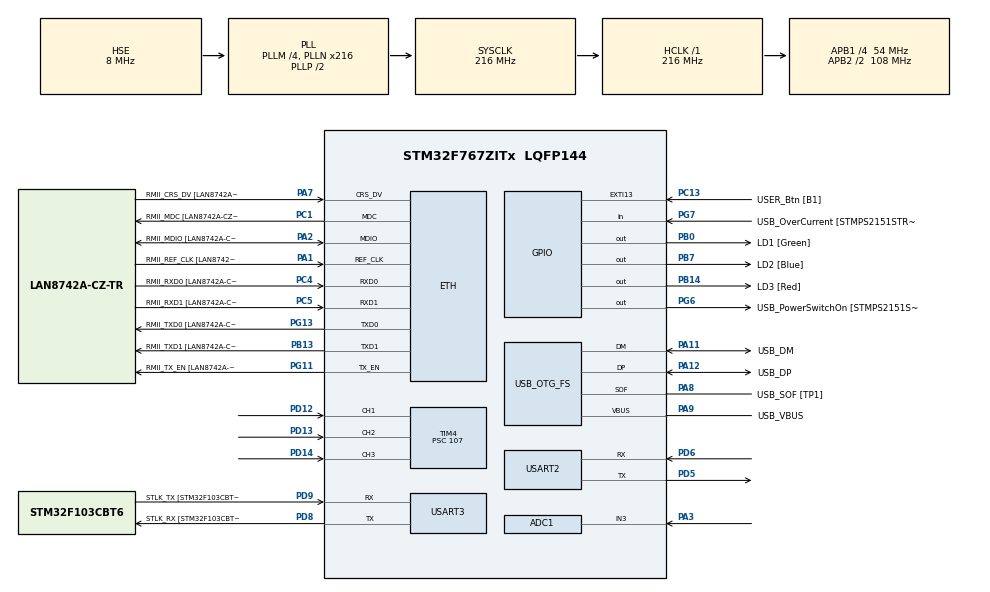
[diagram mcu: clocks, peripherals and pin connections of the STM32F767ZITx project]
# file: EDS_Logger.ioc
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ADC1.Channel-0\#ChannelRegularConversion=ADC_CHANNEL_3
ADC1.ClockPrescaler=ADC_CLOCK_SYNC_PCLK_DIV8
ADC1.ContinuousConvMode=ENABLE
ADC1.DMAContinuousRequests=ENABLE
ADC1.EOCSelection=ADC_EOC_SEQ_CONV
ADC1.ExternalTrigConv=ADC_EXTERNALTRIGCONV_T2_TRGO
ADC1.NbrOfConversion=1
ADC1.NbrOfConversionFlag=1
ADC1.Rank-0\#ChannelRegularConversion=1
ADC1.SamplingTime-0\#ChannelRegularConversion=ADC_SAMPLETIME_84CYCLES
ADC1.ScanConvMode=ADC_SCAN_ENABLE
ADC1.master=1
Dma.ADC1.0.Direction=DMA_PERIPH_TO_MEMORY
Dma.ADC1.0.FIFOMode=DMA_FIFOMODE_DISABLE
Dma.ADC1.0.Instance=DMA2_Stream0
Dma.ADC1.0.MemDataAlignment=DMA_MDATAALIGN_WORD
Dma.ADC1.0.MemInc=DMA_MINC_ENABLE
Dma.ADC1.0.Mode=DMA_CIRCULAR
Dma.ADC1.0.PeriphDataAlignment=DMA_PDATAALIGN_WORD
Dma.ADC1.0.PeriphInc=DMA_PINC_DISABLE
Dma.ADC1.0.Priority=DMA_PRIORITY_HIGH
Dma.Request0=ADC1
Dma.Request1=USART2_RX
Dma.Request2=USART2_TX
Dma.USART2_RX.1.Direction=DMA_PERIPH_TO_MEMORY
Dma.USART2_RX.1.FIFOMode=DMA_FIFOMODE_DISABLE
Dma.USART2_RX.1.Instance=DMA1_Stream5
Dma.USART2_RX.1.MemDataAlignment=DMA_MDATAALIGN_BYTE
Dma.USART2_RX.1.MemInc=DMA_MINC_ENABLE
Dma.USART2_RX.1.Mode=DMA_CIRCULAR
Dma.USART2_RX.1.PeriphDataAlignment=DMA_PDATAALIGN_BYTE
Dma.USART2_RX.1.PeriphInc=DMA_PINC_DISABLE
Dma.USART2_RX.1.Priority=DMA_PRIORITY_LOW
Dma.USART2_TX.2.Direction=DMA_MEMORY_TO_PERIPH
Dma.USART2_TX.2.FIFOMode=DMA_FIFOMODE_DISABLE
Dma.USART2_TX.2.Instance=DMA1_Stream6
Dma.USART2_TX.2.MemDataAlignment=DMA_MDATAALIGN_BYTE
Dma.USART2_TX.2.MemInc=DMA_MINC_ENABLE
Dma.USART2_TX.2.Mode=DMA_NORMAL
Dma.USART2_TX.2.PeriphDataAlignment=DMA_PDATAALIGN_BYTE
Dma.USART2_TX.2.PeriphInc=DMA_PINC_DISABLE
Dma.USART2_TX.2.Priority=DMA_PRIORITY_VERY_HIGH
ETH.MediaInterface=HAL_ETH_RMII_MODE
ETH.PHY_Name=LAN8742A_PHY_ADDRESS
ETH.PHY_Value=0
ETH.PhyAddress=0
Mcu.Family=STM32F7
Mcu.Name=STM32F767ZITx
Mcu.Package=LQFP144
NVIC.DMA1_Stream5_IRQn=true\:1\:0\:true\:false\:true\:false\:true\:true
NVIC.DMA1_Stream6_IRQn=true\:1\:0\:true\:false\:true\:false\:true\:true
NVIC.DMA2_Stream0_IRQn=true\:1\:0\:true\:false\:true\:false\:true\:true
NVIC.OTG_FS_IRQn=true\:0\:0\:false\:false\:true\:false\:true\:true
NVIC.PriorityGroup=NVIC_PRIORITYGROUP_4
NVIC.TIM2_IRQn=true\:1\:0\:true\:false\:true\:true\:true\:true
NVIC.TIM3_IRQn=true\:1\:0\:true\:false\:true\:true\:true\:true
NVIC.TIM4_IRQn=true\:0\:0\:false\:false\:true\:true\:true\:true
NVIC.USART2_IRQn=true\:1\:0\:true\:false\:true\:true\:true\:true
PA1.GPIO_Label=RMII_REF_CLK [LAN8742A-CZ-TR_REFCLK0]
PA1.Mode=RMII
PA1.Signal=ETH_REF_CLK
PA10.GPIO_Label=USB_ID
PA10.Signal=USB_OTG_FS_ID
PA11.GPIO_Label=USB_DM
PA11.Mode=Device_Only
PA11.Signal=USB_OTG_FS_DM
PA12.GPIO_Label=USB_DP
PA12.Mode=Device_Only
PA12.Signal=USB_OTG_FS_DP
PA13.GPIO_Label=TMS
PA13.Mode=Serial_Wire
PA13.Signal=SYS_JTMS-SWDIO
PA14.GPIO_Label=TCK
PA14.Mode=Serial_Wire
PA14.Signal=SYS_JTCK-SWCLK
PA2.GPIO_Label=RMII_MDIO [LAN8742A-CZ-TR_MDIO]
PA2.Mode=RMII
PA2.Signal=ETH_MDIO
PA3.Signal=ADCx_IN3
PA7.GPIO_Label=RMII_CRS_DV [LAN8742A-CZ-TR_CRS_DV]
PA7.Mode=RMII
PA7.Signal=ETH_CRS_DV
PA8.GPIO_Label=USB_SOF [TP1]
PA8.Mode=Activate_SOF_FS
PA8.Signal=USB_OTG_FS_SOF
PA9.GPIO_Label=USB_VBUS
PA9.Mode=Activate_VBUS
PA9.Signal=USB_OTG_FS_VBUS
PB0.GPIO_Label=LD1 [Green]
PB0.Signal=GPIO_Output
PB13.GPIO_Label=RMII_TXD1 [LAN8742A-CZ-TR_TXD1]
PB13.Mode=RMII
PB13.Signal=ETH_TXD1
PB14.GPIO_Label=LD3 [Red]
PB14.Signal=GPIO_Output
PB3.GPIO_Label=SWO
PB3.Signal=SYS_JTDO-SWO
PB7.GPIO_Label=LD2 [Blue]
PB7.Signal=GPIO_Output
PC1.GPIO_Label=RMII_MDC [LAN8742A-CZ-TR_MDC]
PC1.Mode=RMII
PC1.Signal=ETH_MDC
PC13.GPIO_Label=USER_Btn [B1]
PC13.Signal=GPXTI13
PC14/OSC32_IN.Mode=LSE-External-Oscillator
PC14/OSC32_IN.Signal=RCC_OSC32_IN
PC15/OSC32_OUT.Mode=LSE-External-Oscillator
PC15/OSC32_OUT.Signal=RCC_OSC32_OUT
PC4.GPIO_Label=RMII_RXD0 [LAN8742A-CZ-TR_RXD0]
PC4.Mode=RMII
PC4.Signal=ETH_RXD0
PC5.GPIO_Label=RMII_RXD1 [LAN8742A-CZ-TR_RXD1]
PC5.Mode=RMII
PC5.Signal=ETH_RXD1
PD12.Signal=S_TIM4_CH1
PD13.Signal=S_TIM4_CH2
PD14.Signal=S_TIM4_CH3
PD5.Mode=Asynchronous
PD5.Signal=USART2_TX
PD6.Mode=Asynchronous
PD6.Signal=USART2_RX
PD8.GPIO_Label=STLK_RX [STM32F103CBT6_PA3]
PD8.Mode=Asynchronous
PD8.Signal=USART3_TX
PD9.GPIO_Label=STLK_TX [STM32F103CBT6_PA2]
PD9.Mode=Asynchronous
PD9.Signal=USART3_RX
PG11.GPIO_Label=RMII_TX_EN [LAN8742A-CZ-TR_TXEN]
PG11.Mode=RMII
PG11.Signal=ETH_TX_EN
PG13.GPIO_Label=RMII_TXD0 [LAN8742A-CZ-TR_TXD0]
PG13.Mode=RMII
PG13.Signal=ETH_TXD0
PG6.GPIO_Label=USB_PowerSwitchOn [STMPS2151STR_EN]
PG6.Signal=GPIO_Output
PG7.GPIO_Label=USB_OverCurrent [STMPS2151STR_FAULT]
PG7.Signal=GPIO_Input
PH0/OSC_IN.GPIO_Label=MCO [STM32F103CBT6_PA8]
PH0/OSC_IN.Mode=HSE-External-Clock-Source
PH0/OSC_IN.Signal=RCC_OSC_IN
PH1/OSC_OUT.Mode=HSE-External-Clock-Source
PH1/OSC_OUT.Signal=RCC_OSC_OUT
ProjectManager.HeapSize=0x200
ProjectManager.StackSize=0x400
ProjectManager.TargetToolchain=STM32CubeIDE
RCC.48MHZClocksFreq_Value=24000000
RCC.AHBFreq_Value=216000000
RCC.APB1CLKDivider=RCC_HCLK_DIV4
RCC.APB1Freq_Value=54000000
RCC.APB1TimFreq_Value=108000000
RCC.APB2CLKDivider=RCC_HCLK_DIV2
RCC.APB2Freq_Value=108000000
RCC.APB2TimFreq_Value=216000000
RCC.CortexFreq_Value=216000000
RCC.HCLKFreq_Value=216000000
RCC.HSE_VALUE=8000000
RCC.HSI_VALUE=16000000
RCC.PLLM=4
RCC.PLLMUL=RCC_PLL_MUL9
RCC.PLLN=216
RCC.PLLQ=9
RCC.PRESCALERUSB=RCC_USBCLKSOURCE_PLL_DIV1_5
RCC.SYSCLKFreq_VALUE=216000000
RCC.SYSCLKSource=RCC_SYSCLKSOURCE_PLLCLK
RCC.SYSCLKSourceVirtual=RCC_SYSCLKSOURCE_PLLCLK
RCC.USBFreq_Value=48000000
RCC.VCOOutputFreq_Value=432000000
SH.ADCx_IN3.0=ADC1_IN3,IN3
SH.S_TIM4_CH1.0=TIM4_CH1,Input_Capture1_from_TI1
SH.S_TIM4_CH2.0=TIM4_CH2,Input_Capture2_from_TI2
SH.S_TIM4_CH3.0=TIM4_CH3,Input_Capture3_from_TI3
TIM2.AutoReloadPreload=TIM_AUTORELOAD_PRELOAD_ENABLE
TIM2.Period=1499
TIM2.Prescaler=71
TIM2.TIM_MasterOutputTrigger=TIM_TRGO_UPDATE
TIM3.AutoReloadPreload=TIM_AUTORELOAD_PRELOAD_ENABLE
TIM3.Period=9
TIM3.Prescaler=10799
TIM4.Channel-Input_Capture1_from_TI1=TIM_CHANNEL_1
TIM4.Channel-Input_Capture2_from_TI2=TIM_CHANNEL_2
TIM4.Channel-Input_Capture3_from_TI3=TIM_CHANNEL_3
TIM4.ICFilter_CH1=15
TIM4.ICFilter_CH2=15
TIM4.ICFilter_CH3=15
TIM4.Prescaler=107
USART2.VirtualMode-Asynchronous=VM_ASYNC
USART3.VirtualMode-Asynchronous=VM_ASYNC
USB_DEVICE.CLASS_NAME_FS=CDC
USB_DEVICE.VirtualMode-CDC_FS=Cdc
USB_DEVICE.VirtualModeFS=Cdc_FS
USB_OTG_FS.VirtualMode=Device_Only
VP_TIM2_VS_ClockSourceINT.Mode=Internal
VP_TIM3_VS_ClockSourceINT.Mode=Internal
VP_TIM4_VS_ClockSourceINT.Mode=Internal
VP_USB_DEVICE_VS_USB_DEVICE_CDC_FS.Mode=CDC_FS
board=NUCLEO-F767ZI

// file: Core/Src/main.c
/* USER CODE BEGIN Header */
/**
 ******************************************************************************
 * @file           : main.c
 * @brief          : Main program body
 ******************************************************************************
 * @attention
 *
 * Copyright (c) 2025 STMicroelectronics.
 * All rights reserved.
 *
 * This software is licensed under terms that can be found in the LICENSE file
 * in the root directory of this software component.
 * If no LICENSE file comes with this software, it is provided AS-IS.
 *
 ******************************************************************************
 */
/* USER CODE END Header */
#include "main.h"
#include "string.h"
#include "usb_device.h"

/* USER CODE BEGIN Includes */
#include "bldc_interface_uart.h"
#include "bldc_interface.h"
#include "usb_comm.h"
#include "motor_speed.h"
#include "data_acquisition.h"
#include "HX711.h"
/* USER CODE END Includes */

#if defined ( __ICCARM__ ) /*!< IAR Compiler */
#pragma location=0x2007c000
ETH_DMADescTypeDef  DMARxDscrTab[ETH_RX_DESC_CNT]; /* Ethernet Rx DMA Descriptors */
#pragma location=0x2007c0a0
ETH_DMADescTypeDef  DMATxDscrTab[ETH_TX_DESC_CNT]; /* Ethernet Tx DMA Descriptors */

#elif defined ( __CC_ARM )  /* MDK ARM Compiler */

__attribute__((at(0x2007c000))) ETH_DMADescTypeDef  DMARxDscrTab[ETH_RX_DESC_CNT]; /* Ethernet Rx DMA Descriptors */
__attribute__((at(0x2007c0a0))) ETH_DMADescTypeDef  DMATxDscrTab[ETH_TX_DESC_CNT]; /* Ethernet Tx DMA Descriptors */

#elif defined ( __GNUC__ ) /* GNU Compiler */

ETH_DMADescTypeDef DMARxDscrTab[ETH_RX_DESC_CNT] __attribute__((section(".RxDecripSection"))); /* Ethernet Rx DMA Descriptors */
ETH_DMADescTypeDef DMATxDscrTab[ETH_TX_DESC_CNT] __attribute__((section(".TxDecripSection")));   /* Ethernet Tx DMA Descriptors */
#endif

ETH_TxPacketConfig TxConfig;

ADC_HandleTypeDef hadc1;
DMA_HandleTypeDef hdma_adc1;

ETH_HandleTypeDef heth;

TIM_HandleTypeDef htim2;
TIM_HandleTypeDef htim3;
TIM_HandleTypeDef htim4;

UART_HandleTypeDef huart2;
UART_HandleTypeDef huart3;
DMA_HandleTypeDef hdma_usart2_rx;
DMA_HandleTypeDef hdma_usart2_tx;

/* USER CODE BEGIN PV */
volatile uint32_t adc_buffer[ADC_BUFFER_SIZE]; // Buffer
extern uint32_t packet_counter; // Add packet counter

HX711 scale;
float first_reading = 0;
float test = 0;
float load_reading =0.0f;
float  load_known = 194.0f;

int32_t test_int32[5] = {0};
/* USER CODE END PV */

void SystemClock_Config(void);
static void MX_GPIO_Init(void);
static void MX_DMA_Init(void);
static void MX_ETH_Init(void);
static void MX_USART3_UART_Init(void);
static void MX_ADC1_Init(void);
static void MX_TIM2_Init(void);
static void MX_TIM3_Init(void);
static void MX_TIM4_Init(void);
static void MX_USART2_UART_Init(void);
/* USER CODE BEGIN PFP */
static HAL_StatusTypeDef ApplicationInit_Sequence(void);				// main before while loop initiazlizations
static void Application(void);												// while loop applications
/* USER CODE END PFP */

/* USER CODE BEGIN 0 */
int32_t tare = 0;
int32_t avg = 0;
int32_t known = 0 ;
float scaler = 0 ;
/* USER CODE END 0 */

int main(void)
{

  /* MCU Configuration--------------------------------------------------------*/

  /* Reset of all peripherals, Initializes the Flash interface and the Systick. */
  HAL_Init();

  /* Configure the system clock */
  SystemClock_Config();

  /* Initialize all configured peripherals */
  MX_GPIO_Init();
  MX_DMA_Init();
  MX_ETH_Init();
  MX_USART3_UART_Init();
  MX_ADC1_Init();
  MX_TIM2_Init();
  MX_TIM3_Init();
  MX_USB_DEVICE_Init();
  MX_TIM4_Init();
  MX_USART2_UART_Init();
  /* USER CODE BEGIN 2 */
	/* Initialize Application Modules */
	if (ApplicationInit_Sequence() != HAL_OK) {
		Error_Handler();
	}

	 HX711_Init(&scale, LOADCELL_DOUT_PORT, LOADCELL_DOUT_PIN,
			 LOADCELL_SCK_PORT, LOADCELL_SCK_PIN, 128);
	HX711_SetScale(&scale,1);
	HX711_Tare(&scale,30);

	first_reading = HX711_GetUnits(&scale,20);
	test = (float)(first_reading)/(load_known);
	HX711_SetScale(&scale,test);

  /* USER CODE END 2 */

  /* Infinite loop */
	while (1)
	{
	first_reading = HX711_GetUnits(&scale,1);
    /* USER CODE BEGIN 3 */
		//Application();
	}
  /* USER CODE END 3 */
}

void SystemClock_Config(void)
{
  RCC_OscInitTypeDef RCC_OscInitStruct = {0};
  RCC_ClkInitTypeDef RCC_ClkInitStruct = {0};

  /** Configure LSE Drive Capability
  */
  HAL_PWR_EnableBkUpAccess();

  /** Configure the main internal regulator output voltage
  */
  __HAL_RCC_PWR_CLK_ENABLE();
  __HAL_PWR_VOLTAGESCALING_CONFIG(PWR_REGULATOR_VOLTAGE_SCALE1);

  /** Initializes the RCC Oscillators according to the specified parameters
  * in the RCC_OscInitTypeDef structure.
  */
  RCC_OscInitStruct.OscillatorType = RCC_OSCILLATORTYPE_HSE;
  RCC_OscInitStruct.HSEState = RCC_HSE_BYPASS;
  RCC_OscInitStruct.PLL.PLLState = RCC_PLL_ON;
  RCC_OscInitStruct.PLL.PLLSource = RCC_PLLSOURCE_HSE;
  RCC_OscInitStruct.PLL.PLLM = 4;
  RCC_OscInitStruct.PLL.PLLN = 216;
  RCC_OscInitStruct.PLL.PLLP = RCC_PLLP_DIV2;
  RCC_OscInitStruct.PLL.PLLQ = 9;
  RCC_OscInitStruct.PLL.PLLR = 2;
  if (HAL_RCC_OscConfig(&RCC_OscInitStruct) != HAL_OK)
  {
    Error_Handler();
  }

  /** Activate the Over-Drive mode
  */
  if (HAL_PWREx_EnableOverDrive() != HAL_OK)
  {
    Error_Handler();
  }

  /** Initializes the CPU, AHB and APB buses clocks
  */
  RCC_ClkInitStruct.ClockType = RCC_CLOCKTYPE_HCLK|RCC_CLOCKTYPE_SYSCLK
                              |RCC_CLOCKTYPE_PCLK1|RCC_CLOCKTYPE_PCLK2;
  RCC_ClkInitStruct.SYSCLKSource = RCC_SYSCLKSOURCE_PLLCLK;
  RCC_ClkInitStruct.AHBCLKDivider = RCC_SYSCLK_DIV1;
  RCC_ClkInitStruct.APB1CLKDivider = RCC_HCLK_DIV4;
  RCC_ClkInitStruct.APB2CLKDivider = RCC_HCLK_DIV2;

  if (HAL_RCC_ClockConfig(&RCC_ClkInitStruct, FLASH_LATENCY_7) != HAL_OK)
  {
    Error_Handler();
  }
}

static void MX_ADC1_Init(void)
{

  ADC_ChannelConfTypeDef sConfig = {0};

  /** Configure the global features of the ADC (Clock, Resolution, Data Alignment and number of conversion)
  */
  hadc1.Instance = ADC1;
  hadc1.Init.ClockPrescaler = ADC_CLOCK_SYNC_PCLK_DIV8;
  hadc1.Init.Resolution = ADC_RESOLUTION_12B;
  hadc1.Init.ScanConvMode = ADC_SCAN_ENABLE;
  hadc1.Init.ContinuousConvMode = ENABLE;
  hadc1.Init.DiscontinuousConvMode = DISABLE;
  hadc1.Init.ExternalTrigConvEdge = ADC_EXTERNALTRIGCONVEDGE_RISING;
  hadc1.Init.ExternalTrigConv = ADC_EXTERNALTRIGCONV_T2_TRGO;
  hadc1.Init.DataAlign = ADC_DATAALIGN_RIGHT;
  hadc1.Init.NbrOfConversion = 5;
  hadc1.Init.DMAContinuousRequests = ENABLE;
  hadc1.Init.EOCSelection = ADC_EOC_SEQ_CONV;
  if (HAL_ADC_Init(&hadc1) != HAL_OK)
  {
    Error_Handler();
  }

  /** Configure for the selected ADC regular channel its corresponding rank in the sequencer and its sample time.
  */
  sConfig.Channel = ADC_CHANNEL_0;
  sConfig.Rank = ADC_REGULAR_RANK_1;
  sConfig.SamplingTime = ADC_SAMPLETIME_84CYCLES;
  if (HAL_ADC_ConfigChannel(&hadc1, &sConfig) != HAL_OK)
  {
    Error_Handler();
  }

  /** Configure for the selected ADC regular channel its corresponding rank in the sequencer and its sample time.
  */
  sConfig.Channel = ADC_CHANNEL_3;
  sConfig.Rank = ADC_REGULAR_RANK_2;
  if (HAL_ADC_ConfigChannel(&hadc1, &sConfig) != HAL_OK)
  {
    Error_Handler();
  }

  /** Configure for the selected ADC regular channel its corresponding rank in the sequencer and its sample time.
  */
  sConfig.Channel = ADC_CHANNEL_4;
  sConfig.Rank = ADC_REGULAR_RANK_3;
  if (HAL_ADC_ConfigChannel(&hadc1, &sConfig) != HAL_OK)
  {
    Error_Handler();
  }

  /** Configure for the selected ADC regular channel its corresponding rank in the sequencer and its sample time.
  */
  sConfig.Channel = ADC_CHANNEL_5;
  sConfig.Rank = ADC_REGULAR_RANK_4;
  if (HAL_ADC_ConfigChannel(&hadc1, &sConfig) != HAL_OK)
  {
    Error_Handler();
  }

  /** Configure for the selected ADC regular channel its corresponding rank in the sequencer and its sample time.
  */
  sConfig.Channel = ADC_CHANNEL_6;
  sConfig.Rank = ADC_REGULAR_RANK_5;
  if (HAL_ADC_ConfigChannel(&hadc1, &sConfig) != HAL_OK)
  {
    Error_Handler();
  }

}

static void MX_ETH_Init(void)
{

   static uint8_t MACAddr[6];

  heth.Instance = ETH;
  MACAddr[0] = 0x00;
  MACAddr[1] = 0x80;
  MACAddr[2] = 0xE1;
  MACAddr[3] = 0x00;
  MACAddr[4] = 0x00;
  MACAddr[5] = 0x00;
  heth.Init.MACAddr = &MACAddr[0];
  heth.Init.MediaInterface = HAL_ETH_RMII_MODE;
  heth.Init.TxDesc = DMATxDscrTab;
  heth.Init.RxDesc = DMARxDscrTab;
  heth.Init.RxBuffLen = 1524;

  if (HAL_ETH_Init(&heth) != HAL_OK)
  {
    Error_Handler();
  }

  memset(&TxConfig, 0 , sizeof(ETH_TxPacketConfig));
  TxConfig.Attributes = ETH_TX_PACKETS_FEATURES_CSUM | ETH_TX_PACKETS_FEATURES_CRCPAD;
  TxConfig.ChecksumCtrl = ETH_CHECKSUM_IPHDR_PAYLOAD_INSERT_PHDR_CALC;
  TxConfig.CRCPadCtrl = ETH_CRC_PAD_INSERT;

}

static void MX_TIM2_Init(void)
{

  TIM_ClockConfigTypeDef sClockSourceConfig = {0};
  TIM_MasterConfigTypeDef sMasterConfig = {0};

  htim2.Instance = TIM2;
  htim2.Init.Prescaler = 71;
  htim2.Init.CounterMode = TIM_COUNTERMODE_UP;
  htim2.Init.Period = 1499;
  htim2.Init.ClockDivision = TIM_CLOCKDIVISION_DIV1;
  htim2.Init.AutoReloadPreload = TIM_AUTORELOAD_PRELOAD_ENABLE;
  if (HAL_TIM_Base_Init(&htim2) != HAL_OK)
  {
    Error_Handler();
  }
  sClockSourceConfig.ClockSource = TIM_CLOCKSOURCE_INTERNAL;
  if (HAL_TIM_ConfigClockSource(&htim2, &sClockSourceConfig) != HAL_OK)
  {
    Error_Handler();
  }
  sMasterConfig.MasterOutputTrigger = TIM_TRGO_UPDATE;
  sMasterConfig.MasterSlaveMode = TIM_MASTERSLAVEMODE_DISABLE;
  if (HAL_TIMEx_MasterConfigSynchronization(&htim2, &sMasterConfig) != HAL_OK)
  {
    Error_Handler();
  }

}

static void MX_TIM3_Init(void)
{

  TIM_ClockConfigTypeDef sClockSourceConfig = {0};
  TIM_MasterConfigTypeDef sMasterConfig = {0};

  htim3.Instance = TIM3;
  htim3.Init.Prescaler = 10799;
  htim3.Init.CounterMode = TIM_COUNTERMODE_UP;
  htim3.Init.Period = 9;
  htim3.Init.ClockDivision = TIM_CLOCKDIVISION_DIV1;
  htim3.Init.AutoReloadPreload = TIM_AUTORELOAD_PRELOAD_ENABLE;
  if (HAL_TIM_Base_Init(&htim3) != HAL_OK)
  {
    Error_Handler();
  }
  sClockSourceConfig.ClockSource = TIM_CLOCKSOURCE_INTERNAL;
  if (HAL_TIM_ConfigClockSource(&htim3, &sClockSourceConfig) != HAL_OK)
  {
    Error_Handler();
  }
  sMasterConfig.MasterOutputTrigger = TIM_TRGO_RESET;
  sMasterConfig.MasterSlaveMode = TIM_MASTERSLAVEMODE_DISABLE;
  if (HAL_TIMEx_MasterConfigSynchronization(&htim3, &sMasterConfig) != HAL_OK)
  {
    Error_Handler();
  }

}

static void MX_TIM4_Init(void)
{

  TIM_ClockConfigTypeDef sClockSourceConfig = {0};
  TIM_MasterConfigTypeDef sMasterConfig = {0};
  TIM_IC_InitTypeDef sConfigIC = {0};

  htim4.Instance = TIM4;
  htim4.Init.Prescaler = 107;
  htim4.Init.CounterMode = TIM_COUNTERMODE_UP;
  htim4.Init.Period = 65535;
  htim4.Init.ClockDivision = TIM_CLOCKDIVISION_DIV1;
  htim4.Init.AutoReloadPreload = TIM_AUTORELOAD_PRELOAD_DISABLE;
  if (HAL_TIM_Base_Init(&htim4) != HAL_OK)
  {
    Error_Handler();
  }
  sClockSourceConfig.ClockSource = TIM_CLOCKSOURCE_INTERNAL;
  if (HAL_TIM_ConfigClockSource(&htim4, &sClockSourceConfig) != HAL_OK)
  {
    Error_Handler();
  }
  if (HAL_TIM_IC_Init(&htim4) != HAL_OK)
  {
    Error_Handler();
  }
  sMasterConfig.MasterOutputTrigger = TIM_TRGO_RESET;
  sMasterConfig.MasterSlaveMode = TIM_MASTERSLAVEMODE_DISABLE;
  if (HAL_TIMEx_MasterConfigSynchronization(&htim4, &sMasterConfig) != HAL_OK)
  {
    Error_Handler();
  }
  sConfigIC.ICPolarity = TIM_INPUTCHANNELPOLARITY_RISING;
  sConfigIC.ICSelection = TIM_ICSELECTION_DIRECTTI;
  sConfigIC.ICPrescaler = TIM_ICPSC_DIV1;
  sConfigIC.ICFilter = 15;
  if (HAL_TIM_IC_ConfigChannel(&htim4, &sConfigIC, TIM_CHANNEL_1) != HAL_OK)
  {
    Error_Handler();
  }
  if (HAL_TIM_IC_ConfigChannel(&htim4, &sConfigIC, TIM_CHANNEL_2) != HAL_OK)
  {
    Error_Handler();
  }
  if (HAL_TIM_IC_ConfigChannel(&htim4, &sConfigIC, TIM_CHANNEL_3) != HAL_OK)
  {
    Error_Handler();
  }

}

static void MX_USART2_UART_Init(void)
{

  huart2.Instance = USART2;
  huart2.Init.BaudRate = 115200;
  huart2.Init.WordLength = UART_WORDLENGTH_8B;
  huart2.Init.StopBits = UART_STOPBITS_1;
  huart2.Init.Parity = UART_PARITY_NONE;
  huart2.Init.Mode = UART_MODE_TX_RX;
  huart2.Init.HwFlowCtl = UART_HWCONTROL_NONE;
  huart2.Init.OverSampling = UART_OVERSAMPLING_16;
  huart2.Init.OneBitSampling = UART_ONE_BIT_SAMPLE_DISABLE;
  huart2.AdvancedInit.AdvFeatureInit = UART_ADVFEATURE_NO_INIT;
  if (HAL_UART_Init(&huart2) != HAL_OK)
  {
    Error_Handler();
  }

}

static void MX_USART3_UART_Init(void)
{

  huart3.Instance = USART3;
  huart3.Init.BaudRate = 115200;
  huart3.Init.WordLength = UART_WORDLENGTH_8B;
  huart3.Init.StopBits = UART_STOPBITS_1;
  huart3.Init.Parity = UART_PARITY_NONE;
  huart3.Init.Mode = UART_MODE_TX_RX;
  huart3.Init.HwFlowCtl = UART_HWCONTROL_NONE;
  huart3.Init.OverSampling = UART_OVERSAMPLING_16;
  huart3.Init.OneBitSampling = UART_ONE_BIT_SAMPLE_DISABLE;
  huart3.AdvancedInit.AdvFeatureInit = UART_ADVFEATURE_NO_INIT;
  if (HAL_UART_Init(&huart3) != HAL_OK)
  {
    Error_Handler();
  }

}

static void MX_DMA_Init(void)
{

  /* DMA controller clock enable */
  __HAL_RCC_DMA2_CLK_ENABLE();
  __HAL_RCC_DMA1_CLK_ENABLE();

  /* DMA interrupt init */
  /* DMA1_Stream5_IRQn interrupt configuration */
  HAL_NVIC_SetPriority(DMA1_Stream5_IRQn, 1, 0);
  HAL_NVIC_EnableIRQ(DMA1_Stream5_IRQn);
  /* DMA1_Stream6_IRQn interrupt configuration */
  HAL_NVIC_SetPriority(DMA1_Stream6_IRQn, 1, 0);
  HAL_NVIC_EnableIRQ(DMA1_Stream6_IRQn);
  /* DMA2_Stream0_IRQn interrupt configuration */
  HAL_NVIC_SetPriority(DMA2_Stream0_IRQn, 1, 0);
  HAL_NVIC_EnableIRQ(DMA2_Stream0_IRQn);

}

static void MX_GPIO_Init(void)
{
  GPIO_InitTypeDef GPIO_InitStruct = {0};

  /* GPIO Ports Clock Enable */
  __HAL_RCC_GPIOC_CLK_ENABLE();
  __HAL_RCC_GPIOH_CLK_ENABLE();
  __HAL_RCC_GPIOA_CLK_ENABLE();
  __HAL_RCC_GPIOB_CLK_ENABLE();
  __HAL_RCC_GPIOF_CLK_ENABLE();
  __HAL_RCC_GPIOE_CLK_ENABLE();
  __HAL_RCC_GPIOD_CLK_ENABLE();
  __HAL_RCC_GPIOG_CLK_ENABLE();

  /*Configure GPIO pin Output Level */
  HAL_GPIO_WritePin(GPIOB, LD1_Pin|LD3_Pin|LD2_Pin|GPIO_PIN_9, GPIO_PIN_RESET);

  /*Configure GPIO pin Output Level */
  HAL_GPIO_WritePin(GPIOF, GPIO_PIN_13, GPIO_PIN_RESET);

  /*Configure GPIO pin Output Level */
  HAL_GPIO_WritePin(USB_PowerSwitchOn_GPIO_Port, USB_PowerSwitchOn_Pin, GPIO_PIN_RESET);

  /*Configure GPIO pin : USER_Btn_Pin */
  GPIO_InitStruct.Pin = USER_Btn_Pin;
  GPIO_InitStruct.Mode = GPIO_MODE_IT_RISING;
  GPIO_InitStruct.Pull = GPIO_NOPULL;
  HAL_GPIO_Init(USER_Btn_GPIO_Port, &GPIO_InitStruct);

  /*Configure GPIO pins : LD1_Pin LD3_Pin LD2_Pin PB9 */
  GPIO_InitStruct.Pin = LD1_Pin|LD3_Pin|LD2_Pin|GPIO_PIN_9;
  GPIO_InitStruct.Mode = GPIO_MODE_OUTPUT_PP;
  GPIO_InitStruct.Pull = GPIO_NOPULL;
  GPIO_InitStruct.Speed = GPIO_SPEED_FREQ_LOW;
  HAL_GPIO_Init(GPIOB, &GPIO_InitStruct);

  /*Configure GPIO pin : PF13 */
  GPIO_InitStruct.Pin = GPIO_PIN_13;
  GPIO_InitStruct.Mode = GPIO_MODE_OUTPUT_PP;
  GPIO_InitStruct.Pull = GPIO_NOPULL;
  GPIO_InitStruct.Speed = GPIO_SPEED_FREQ_LOW;
  HAL_GPIO_Init(GPIOF, &GPIO_InitStruct);

  /*Configure GPIO pin : PE9 */
  GPIO_InitStruct.Pin = GPIO_PIN_9;
  GPIO_InitStruct.Mode = GPIO_MODE_INPUT;
  GPIO_InitStruct.Pull = GPIO_NOPULL;
  HAL_GPIO_Init(GPIOE, &GPIO_InitStruct);

  /*Configure GPIO pin : PD15 */
  GPIO_InitStruct.Pin = GPIO_PIN_15;
  GPIO_InitStruct.Mode = GPIO_MODE_INPUT;
  GPIO_InitStruct.Pull = GPIO_NOPULL;
  HAL_GPIO_Init(GPIOD, &GPIO_InitStruct);

  /*Configure GPIO pin : USB_PowerSwitchOn_Pin */
  GPIO_InitStruct.Pin = USB_PowerSwitchOn_Pin;
  GPIO_InitStruct.Mode = GPIO_MODE_OUTPUT_PP;
  GPIO_InitStruct.Pull = GPIO_NOPULL;
  GPIO_InitStruct.Speed = GPIO_SPEED_FREQ_LOW;
  HAL_GPIO_Init(USB_PowerSwitchOn_GPIO_Port, &GPIO_InitStruct);

  /*Configure GPIO pin : USB_OverCurrent_Pin */
  GPIO_InitStruct.Pin = USB_OverCurrent_Pin;
  GPIO_InitStruct.Mode = GPIO_MODE_INPUT;
  GPIO_InitStruct.Pull = GPIO_NOPULL;
  HAL_GPIO_Init(USB_OverCurrent_GPIO_Port, &GPIO_InitStruct);

}

/* USER CODE BEGIN 4 */

static HAL_StatusTypeDef ApplicationInit_Sequence(void)
{
	/* Start ADC with DMA */
	if (HAL_ADC_Start_DMA(&hadc1, (uint32_t*)adc_buffer, ADC_BUFFER_SIZE) != HAL_OK) {
		return HAL_ERROR;
	}

	/* Initialize motor speed monitoring */
	if (MotorSpeed_Init(&htim4) != HAL_OK) {
		return HAL_ERROR;
	}

	/* Start timer input capture for all channels */
	if (HAL_TIM_IC_Start_IT(&htim4, TIM_CHANNEL_1) != HAL_OK) return HAL_ERROR;
	if (HAL_TIM_IC_Start_IT(&htim4, TIM_CHANNEL_2) != HAL_OK) return HAL_ERROR;
	if (HAL_TIM_IC_Start_IT(&htim4, TIM_CHANNEL_3) != HAL_OK) return HAL_ERROR;

	/* Initialize data acquisition system */
	if (DataAcq_Init() != HAL_OK) {
		return HAL_ERROR;
	}

	/* Initialize BLDC interface */
	bldc_interface_uart_init(send_packet);

	/* Initialize Timer 2 */
	HAL_TIM_Base_Start(&htim2);

	return HAL_OK;
}

static void Application(void)
{
	usb_transmit_task();

}

/* USER CODE END 4 */

void Error_Handler(void)
{
	__disable_irq();
	while (1)
	{
	}
}
